VERSION 5.7 ;
  NOWIREEXTENSIONATPIN ON ;
  DIVIDERCHAR "/" ;
  BUSBITCHARS "[]" ;
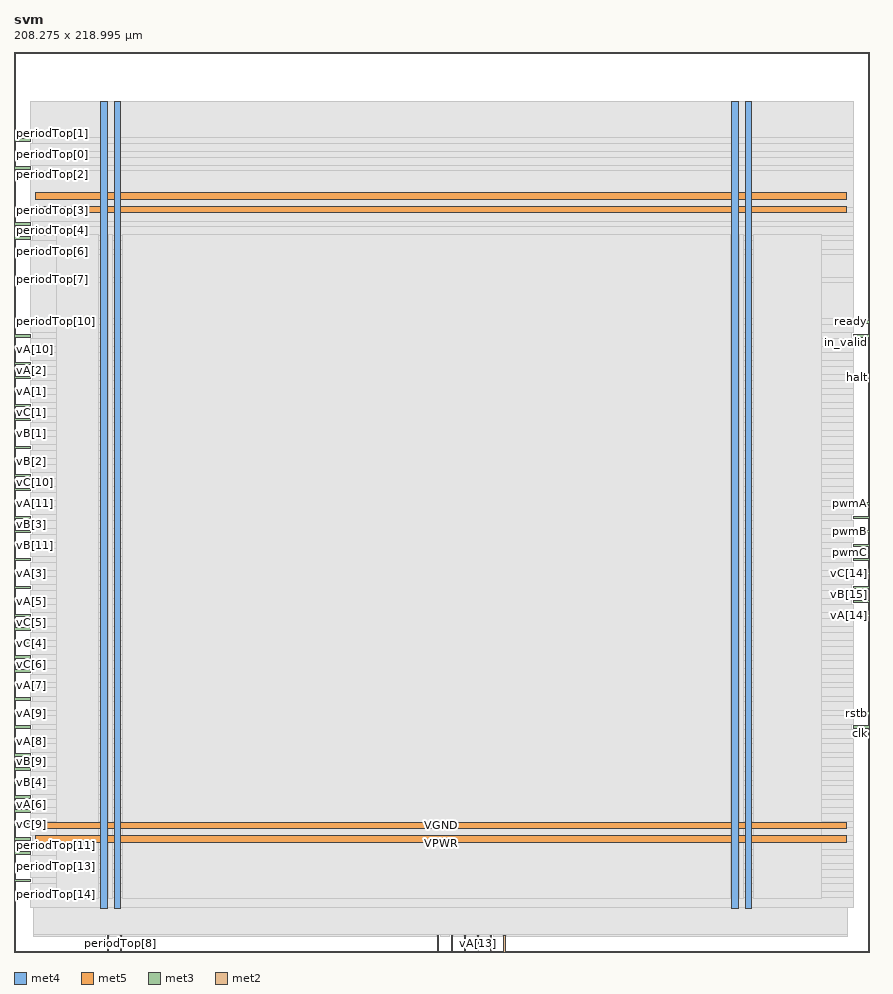
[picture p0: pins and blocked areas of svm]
MACRO svm
  CLASS BLOCK ;
  FOREIGN svm ;
  ORIGIN 0.000 0.000 ;
  SIZE 208.275 BY 218.995 ;
  PIN VGND
    DIRECTION INOUT ;
    USE GROUND ;
    PORT
      LAYER met4 ;
        RECT 24.340 10.640 25.940 206.960 ;
    END
    PORT
      LAYER met4 ;
        RECT 177.940 10.640 179.540 206.960 ;
    END
    PORT
      LAYER met5 ;
        RECT 5.280 30.030 202.640 31.630 ;
    END
    PORT
      LAYER met5 ;
        RECT 5.280 183.210 202.640 184.810 ;
    END
  END VGND
  PIN VPWR
    DIRECTION INOUT ;
    USE POWER ;
    PORT
      LAYER met4 ;
        RECT 21.040 10.640 22.640 206.960 ;
    END
    PORT
      LAYER met4 ;
        RECT 174.640 10.640 176.240 206.960 ;
    END
    PORT
      LAYER met5 ;
        RECT 5.280 26.730 202.640 28.330 ;
    END
    PORT
      LAYER met5 ;
        RECT 5.280 179.910 202.640 181.510 ;
    END
  END VPWR
  PIN clk
    DIRECTION INPUT ;
    USE SIGNAL ;
    ANTENNAGATEAREA 0.852000 ;
    PORT
      LAYER met3 ;
        RECT 204.275 54.440 208.275 55.040 ;
    END
  END clk
  PIN halt
    DIRECTION OUTPUT ;
    USE SIGNAL ;
    ANTENNADIFFAREA 0.445500 ;
    PORT
      LAYER met3 ;
        RECT 204.275 139.440 208.275 140.040 ;
    END
  END halt
  PIN in_valid
    DIRECTION INPUT ;
    USE SIGNAL ;
    ANTENNAGATEAREA 0.196500 ;
    PORT
      LAYER met3 ;
        RECT 204.275 149.640 208.275 150.240 ;
    END
  END in_valid
  PIN periodTop[0]
    DIRECTION INPUT ;
    USE SIGNAL ;
    ANTENNAGATEAREA 0.196500 ;
    PORT
      LAYER met3 ;
        RECT 0.000 193.840 4.000 194.440 ;
    END
  END periodTop[0]
  PIN periodTop[10]
    DIRECTION INPUT ;
    USE SIGNAL ;
    ANTENNAGATEAREA 0.196500 ;
    PORT
      LAYER met3 ;
        RECT 0.000 153.040 4.000 153.640 ;
    END
  END periodTop[10]
  PIN periodTop[11]
    DIRECTION INPUT ;
    USE SIGNAL ;
    ANTENNAGATEAREA 0.196500 ;
    PORT
      LAYER met3 ;
        RECT 0.000 27.240 4.000 27.840 ;
    END
  END periodTop[11]
  PIN periodTop[12]
    DIRECTION INPUT ;
    USE SIGNAL ;
    ANTENNAGATEAREA 0.196500 ;
    PORT
      LAYER met3 ;
        RECT 0.000 23.840 4.000 24.440 ;
    END
  END periodTop[12]
  PIN periodTop[13]
    DIRECTION INPUT ;
    USE SIGNAL ;
    ANTENNAGATEAREA 0.196500 ;
    PORT
      LAYER met3 ;
        RECT 0.000 20.440 4.000 21.040 ;
    END
  END periodTop[13]
  PIN periodTop[14]
    DIRECTION INPUT ;
    USE SIGNAL ;
    ANTENNAGATEAREA 0.742500 ;
    PORT
      LAYER met3 ;
        RECT 0.000 13.640 4.000 14.240 ;
    END
  END periodTop[14]
  PIN periodTop[15]
    DIRECTION INPUT ;
    USE SIGNAL ;
    ANTENNAGATEAREA 0.196500 ;
    PORT
      LAYER met3 ;
        RECT 0.000 17.040 4.000 17.640 ;
    END
  END periodTop[15]
  PIN periodTop[1]
    DIRECTION INPUT ;
    USE SIGNAL ;
    ANTENNAGATEAREA 0.196500 ;
    PORT
      LAYER met3 ;
        RECT 0.000 197.240 4.000 197.840 ;
    END
  END periodTop[1]
  PIN periodTop[2]
    DIRECTION INPUT ;
    USE SIGNAL ;
    ANTENNAGATEAREA 0.196500 ;
    PORT
      LAYER met3 ;
        RECT 0.000 190.440 4.000 191.040 ;
    END
  END periodTop[2]
  PIN periodTop[3]
    DIRECTION INPUT ;
    USE SIGNAL ;
    ANTENNAGATEAREA 0.213000 ;
    PORT
      LAYER met3 ;
        RECT 0.000 180.240 4.000 180.840 ;
    END
  END periodTop[3]
  PIN periodTop[4]
    DIRECTION INPUT ;
    USE SIGNAL ;
    ANTENNAGATEAREA 0.196500 ;
    PORT
      LAYER met3 ;
        RECT 0.000 176.840 4.000 177.440 ;
    END
  END periodTop[4]
  PIN periodTop[5]
    DIRECTION INPUT ;
    USE SIGNAL ;
    ANTENNAGATEAREA 0.213000 ;
    PORT
      LAYER met3 ;
        RECT 0.000 173.440 4.000 174.040 ;
    END
  END periodTop[5]
  PIN periodTop[6]
    DIRECTION INPUT ;
    USE SIGNAL ;
    ANTENNAGATEAREA 0.213000 ;
    PORT
      LAYER met3 ;
        RECT 0.000 170.040 4.000 170.640 ;
    END
  END periodTop[6]
  PIN periodTop[7]
    DIRECTION INPUT ;
    USE SIGNAL ;
    ANTENNAGATEAREA 0.196500 ;
    PORT
      LAYER met3 ;
        RECT 0.000 163.240 4.000 163.840 ;
    END
  END periodTop[7]
  PIN periodTop[8]
    DIRECTION INPUT ;
    USE SIGNAL ;
    ANTENNAGATEAREA 0.196500 ;
    PORT
      LAYER met2 ;
        RECT 25.850 0.000 26.130 4.000 ;
    END
  END periodTop[8]
  PIN periodTop[9]
    DIRECTION INPUT ;
    USE SIGNAL ;
    ANTENNAGATEAREA 0.196500 ;
    PORT
      LAYER met2 ;
        RECT 22.630 0.000 22.910 4.000 ;
    END
  END periodTop[9]
  PIN pwmA
    DIRECTION OUTPUT ;
    USE SIGNAL ;
    ANTENNADIFFAREA 0.445500 ;
    PORT
      LAYER met3 ;
        RECT 204.275 108.840 208.275 109.440 ;
    END
  END pwmA
  PIN pwmB
    DIRECTION OUTPUT ;
    USE SIGNAL ;
    ANTENNADIFFAREA 0.795200 ;
    PORT
      LAYER met3 ;
        RECT 204.275 102.040 208.275 102.640 ;
    END
  END pwmB
  PIN pwmC
    DIRECTION OUTPUT ;
    USE SIGNAL ;
    ANTENNADIFFAREA 0.445500 ;
    PORT
      LAYER met3 ;
        RECT 204.275 98.640 208.275 99.240 ;
    END
  END pwmC
  PIN ready
    DIRECTION OUTPUT ;
    USE SIGNAL ;
    ANTENNADIFFAREA 0.445500 ;
    PORT
      LAYER met3 ;
        RECT 204.275 153.040 208.275 153.640 ;
    END
  END ready
  PIN rstb
    DIRECTION INPUT ;
    USE SIGNAL ;
    ANTENNAGATEAREA 0.196500 ;
    PORT
      LAYER met3 ;
        RECT 204.275 57.840 208.275 58.440 ;
    END
  END rstb
  PIN vA[0]
    DIRECTION INPUT ;
    USE SIGNAL ;
    ANTENNAGATEAREA 0.196500 ;
    PORT
      LAYER met3 ;
        RECT 0.000 149.640 4.000 150.240 ;
    END
  END vA[0]
  PIN vA[10]
    DIRECTION INPUT ;
    USE SIGNAL ;
    ANTENNAGATEAREA 0.196500 ;
    PORT
      LAYER met3 ;
        RECT 0.000 146.240 4.000 146.840 ;
    END
  END vA[10]
  PIN vA[11]
    DIRECTION INPUT ;
    USE SIGNAL ;
    ANTENNAGATEAREA 0.196500 ;
    PORT
      LAYER met3 ;
        RECT 0.000 108.840 4.000 109.440 ;
    END
  END vA[11]
  PIN vA[12]
    DIRECTION INPUT ;
    USE SIGNAL ;
    ANTENNAGATEAREA 0.196500 ;
    PORT
      LAYER met2 ;
        RECT 103.130 0.000 103.410 4.000 ;
    END
  END vA[12]
  PIN vA[13]
    DIRECTION INPUT ;
    USE SIGNAL ;
    ANTENNAGATEAREA 0.196500 ;
    PORT
      LAYER met2 ;
        RECT 112.790 0.000 113.070 4.000 ;
    END
  END vA[13]
  PIN vA[14]
    DIRECTION INPUT ;
    USE SIGNAL ;
    ANTENNAGATEAREA 0.196500 ;
    PORT
      LAYER met3 ;
        RECT 204.275 81.640 208.275 82.240 ;
    END
  END vA[14]
  PIN vA[15]
    DIRECTION INPUT ;
    USE SIGNAL ;
    ANTENNAGATEAREA 0.196500 ;
    PORT
      LAYER met3 ;
        RECT 204.275 95.240 208.275 95.840 ;
    END
  END vA[15]
  PIN vA[1]
    DIRECTION INPUT ;
    USE SIGNAL ;
    ANTENNAGATEAREA 0.196500 ;
    PORT
      LAYER met3 ;
        RECT 0.000 136.040 4.000 136.640 ;
    END
  END vA[1]
  PIN vA[2]
    DIRECTION INPUT ;
    USE SIGNAL ;
    ANTENNAGATEAREA 0.196500 ;
    PORT
      LAYER met3 ;
        RECT 0.000 142.840 4.000 143.440 ;
    END
  END vA[2]
  PIN vA[3]
    DIRECTION INPUT ;
    USE SIGNAL ;
    ANTENNAGATEAREA 0.196500 ;
    PORT
      LAYER met3 ;
        RECT 0.000 91.840 4.000 92.440 ;
    END
  END vA[3]
  PIN vA[4]
    DIRECTION INPUT ;
    USE SIGNAL ;
    ANTENNAGATEAREA 0.196500 ;
    PORT
      LAYER met3 ;
        RECT 0.000 78.240 4.000 78.840 ;
    END
  END vA[4]
  PIN vA[5]
    DIRECTION INPUT ;
    USE SIGNAL ;
    ANTENNAGATEAREA 0.196500 ;
    PORT
      LAYER met3 ;
        RECT 0.000 85.040 4.000 85.640 ;
    END
  END vA[5]
  PIN vA[6]
    DIRECTION INPUT ;
    USE SIGNAL ;
    ANTENNAGATEAREA 0.196500 ;
    PORT
      LAYER met3 ;
        RECT 0.000 34.040 4.000 34.640 ;
    END
  END vA[6]
  PIN vA[7]
    DIRECTION INPUT ;
    USE SIGNAL ;
    ANTENNAGATEAREA 0.196500 ;
    PORT
      LAYER met3 ;
        RECT 0.000 64.640 4.000 65.240 ;
    END
  END vA[7]
  PIN vA[8]
    DIRECTION INPUT ;
    USE SIGNAL ;
    ANTENNAGATEAREA 0.196500 ;
    PORT
      LAYER met3 ;
        RECT 0.000 51.040 4.000 51.640 ;
    END
  END vA[8]
  PIN vA[9]
    DIRECTION INPUT ;
    USE SIGNAL ;
    ANTENNAGATEAREA 0.196500 ;
    PORT
      LAYER met3 ;
        RECT 0.000 57.840 4.000 58.440 ;
    END
  END vA[9]
  PIN vB[0]
    DIRECTION INPUT ;
    USE SIGNAL ;
    ANTENNAGATEAREA 0.196500 ;
    PORT
      LAYER met3 ;
        RECT 0.000 132.640 4.000 133.240 ;
    END
  END vB[0]
  PIN vB[10]
    DIRECTION INPUT ;
    USE SIGNAL ;
    ANTENNAGATEAREA 0.196500 ;
    PORT
      LAYER met3 ;
        RECT 0.000 112.240 4.000 112.840 ;
    END
  END vB[10]
  PIN vB[11]
    DIRECTION INPUT ;
    USE SIGNAL ;
    ANTENNAGATEAREA 0.196500 ;
    PORT
      LAYER met3 ;
        RECT 0.000 98.640 4.000 99.240 ;
    END
  END vB[11]
  PIN vB[12]
    DIRECTION INPUT ;
    USE SIGNAL ;
    ANTENNAGATEAREA 0.196500 ;
    PORT
      LAYER met2 ;
        RECT 106.350 0.000 106.630 4.000 ;
    END
  END vB[12]
  PIN vB[13]
    DIRECTION INPUT ;
    USE SIGNAL ;
    ANTENNAGATEAREA 0.196500 ;
    PORT
      LAYER met2 ;
        RECT 119.230 0.000 119.510 4.000 ;
    END
  END vB[13]
  PIN vB[14]
    DIRECTION INPUT ;
    USE SIGNAL ;
    ANTENNAGATEAREA 0.196500 ;
    PORT
      LAYER met3 ;
        RECT 204.275 105.440 208.275 106.040 ;
    END
  END vB[14]
  PIN vB[15]
    DIRECTION INPUT ;
    USE SIGNAL ;
    ANTENNAGATEAREA 0.196500 ;
    PORT
      LAYER met3 ;
        RECT 204.275 85.040 208.275 85.640 ;
    END
  END vB[15]
  PIN vB[1]
    DIRECTION INPUT ;
    USE SIGNAL ;
    ANTENNAGATEAREA 0.196500 ;
    PORT
      LAYER met3 ;
        RECT 0.000 125.840 4.000 126.440 ;
    END
  END vB[1]
  PIN vB[2]
    DIRECTION INPUT ;
    USE SIGNAL ;
    ANTENNAGATEAREA 0.196500 ;
    PORT
      LAYER met3 ;
        RECT 0.000 119.040 4.000 119.640 ;
    END
  END vB[2]
  PIN vB[3]
    DIRECTION INPUT ;
    USE SIGNAL ;
    ANTENNAGATEAREA 0.196500 ;
    PORT
      LAYER met3 ;
        RECT 0.000 102.040 4.000 102.640 ;
    END
  END vB[3]
  PIN vB[4]
    DIRECTION INPUT ;
    USE SIGNAL ;
    ANTENNAGATEAREA 0.196500 ;
    PORT
      LAYER met3 ;
        RECT 0.000 40.840 4.000 41.440 ;
    END
  END vB[4]
  PIN vB[5]
    DIRECTION INPUT ;
    USE SIGNAL ;
    ANTENNAGATEAREA 0.196500 ;
    PORT
      LAYER met3 ;
        RECT 0.000 88.440 4.000 89.040 ;
    END
  END vB[5]
  PIN vB[6]
    DIRECTION INPUT ;
    USE SIGNAL ;
    ANTENNAGATEAREA 0.196500 ;
    PORT
      LAYER met3 ;
        RECT 0.000 61.240 4.000 61.840 ;
    END
  END vB[6]
  PIN vB[7]
    DIRECTION INPUT ;
    USE SIGNAL ;
    ANTENNAGATEAREA 0.196500 ;
    PORT
      LAYER met3 ;
        RECT 0.000 37.440 4.000 38.040 ;
    END
  END vB[7]
  PIN vB[8]
    DIRECTION INPUT ;
    USE SIGNAL ;
    ANTENNAGATEAREA 0.196500 ;
    PORT
      LAYER met3 ;
        RECT 0.000 54.440 4.000 55.040 ;
    END
  END vB[8]
  PIN vB[9]
    DIRECTION INPUT ;
    USE SIGNAL ;
    ANTENNAGATEAREA 0.196500 ;
    PORT
      LAYER met3 ;
        RECT 0.000 47.640 4.000 48.240 ;
    END
  END vB[9]
  PIN vC[0]
    DIRECTION INPUT ;
    USE SIGNAL ;
    ANTENNAGATEAREA 0.213000 ;
    PORT
      LAYER met3 ;
        RECT 0.000 139.440 4.000 140.040 ;
    END
  END vC[0]
  PIN vC[10]
    DIRECTION INPUT ;
    USE SIGNAL ;
    ANTENNAGATEAREA 0.196500 ;
    PORT
      LAYER met3 ;
        RECT 0.000 115.640 4.000 116.240 ;
    END
  END vC[10]
  PIN vC[11]
    DIRECTION INPUT ;
    USE SIGNAL ;
    ANTENNAGATEAREA 0.196500 ;
    PORT
      LAYER met3 ;
        RECT 0.000 95.240 4.000 95.840 ;
    END
  END vC[11]
  PIN vC[12]
    DIRECTION INPUT ;
    USE SIGNAL ;
    ANTENNAGATEAREA 0.196500 ;
    PORT
      LAYER met2 ;
        RECT 109.570 0.000 109.850 4.000 ;
    END
  END vC[12]
  PIN vC[13]
    DIRECTION INPUT ;
    USE SIGNAL ;
    ANTENNAGATEAREA 0.196500 ;
    PORT
      LAYER met2 ;
        RECT 116.010 0.000 116.290 4.000 ;
    END
  END vC[13]
  PIN vC[14]
    DIRECTION INPUT ;
    USE SIGNAL ;
    ANTENNAGATEAREA 0.196500 ;
    PORT
      LAYER met3 ;
        RECT 204.275 91.840 208.275 92.440 ;
    END
  END vC[14]
  PIN vC[15]
    DIRECTION INPUT ;
    USE SIGNAL ;
    ANTENNAGATEAREA 0.196500 ;
    PORT
      LAYER met3 ;
        RECT 204.275 88.440 208.275 89.040 ;
    END
  END vC[15]
  PIN vC[1]
    DIRECTION INPUT ;
    USE SIGNAL ;
    ANTENNAGATEAREA 0.213000 ;
    PORT
      LAYER met3 ;
        RECT 0.000 129.240 4.000 129.840 ;
    END
  END vC[1]
  PIN vC[2]
    DIRECTION INPUT ;
    USE SIGNAL ;
    ANTENNAGATEAREA 0.196500 ;
    PORT
      LAYER met3 ;
        RECT 0.000 122.440 4.000 123.040 ;
    END
  END vC[2]
  PIN vC[3]
    DIRECTION INPUT ;
    USE SIGNAL ;
    ANTENNAGATEAREA 0.196500 ;
    PORT
      LAYER met3 ;
        RECT 0.000 105.440 4.000 106.040 ;
    END
  END vC[3]
  PIN vC[4]
    DIRECTION INPUT ;
    USE SIGNAL ;
    ANTENNAGATEAREA 0.196500 ;
    PORT
      LAYER met3 ;
        RECT 0.000 74.840 4.000 75.440 ;
    END
  END vC[4]
  PIN vC[5]
    DIRECTION INPUT ;
    USE SIGNAL ;
    ANTENNAGATEAREA 0.196500 ;
    PORT
      LAYER met3 ;
        RECT 0.000 81.640 4.000 82.240 ;
    END
  END vC[5]
  PIN vC[6]
    DIRECTION INPUT ;
    USE SIGNAL ;
    ANTENNAGATEAREA 0.196500 ;
    PORT
      LAYER met3 ;
        RECT 0.000 68.040 4.000 68.640 ;
    END
  END vC[6]
  PIN vC[7]
    DIRECTION INPUT ;
    USE SIGNAL ;
    ANTENNAGATEAREA 0.196500 ;
    PORT
      LAYER met3 ;
        RECT 0.000 71.440 4.000 72.040 ;
    END
  END vC[7]
  PIN vC[8]
    DIRECTION INPUT ;
    USE SIGNAL ;
    ANTENNAGATEAREA 0.196500 ;
    PORT
      LAYER met3 ;
        RECT 0.000 44.240 4.000 44.840 ;
    END
  END vC[8]
  PIN vC[9]
    DIRECTION INPUT ;
    USE SIGNAL ;
    ANTENNAGATEAREA 0.213000 ;
    PORT
      LAYER met3 ;
        RECT 0.000 30.640 4.000 31.240 ;
    END
  END vC[9]
  OBS
      LAYER li1 ;
        RECT 5.520 10.795 202.400 206.805 ;
      LAYER met1 ;
        RECT 4.670 10.240 202.790 206.960 ;
      LAYER met2 ;
        RECT 4.690 4.280 202.770 206.905 ;
        RECT 4.690 3.670 22.350 4.280 ;
        RECT 23.190 3.670 25.570 4.280 ;
        RECT 26.410 3.670 102.850 4.280 ;
        RECT 103.690 3.670 106.070 4.280 ;
        RECT 106.910 3.670 109.290 4.280 ;
        RECT 110.130 3.670 112.510 4.280 ;
        RECT 113.350 3.670 115.730 4.280 ;
        RECT 116.570 3.670 118.950 4.280 ;
        RECT 119.790 3.670 202.770 4.280 ;
      LAYER met3 ;
        RECT 3.990 198.240 204.275 206.885 ;
        RECT 4.400 196.840 204.275 198.240 ;
        RECT 3.990 194.840 204.275 196.840 ;
        RECT 4.400 193.440 204.275 194.840 ;
        RECT 3.990 191.440 204.275 193.440 ;
        RECT 4.400 190.040 204.275 191.440 ;
        RECT 3.990 181.240 204.275 190.040 ;
        RECT 4.400 179.840 204.275 181.240 ;
        RECT 3.990 177.840 204.275 179.840 ;
        RECT 4.400 176.440 204.275 177.840 ;
        RECT 3.990 174.440 204.275 176.440 ;
        RECT 4.400 173.040 204.275 174.440 ;
        RECT 3.990 171.040 204.275 173.040 ;
        RECT 4.400 169.640 204.275 171.040 ;
        RECT 3.990 164.240 204.275 169.640 ;
        RECT 4.400 162.840 204.275 164.240 ;
        RECT 3.990 154.040 204.275 162.840 ;
        RECT 4.400 152.640 203.875 154.040 ;
        RECT 3.990 150.640 204.275 152.640 ;
        RECT 4.400 149.240 203.875 150.640 ;
        RECT 3.990 147.240 204.275 149.240 ;
        RECT 4.400 145.840 204.275 147.240 ;
        RECT 3.990 143.840 204.275 145.840 ;
        RECT 4.400 142.440 204.275 143.840 ;
        RECT 3.990 140.440 204.275 142.440 ;
        RECT 4.400 139.040 203.875 140.440 ;
        RECT 3.990 137.040 204.275 139.040 ;
        RECT 4.400 135.640 204.275 137.040 ;
        RECT 3.990 133.640 204.275 135.640 ;
        RECT 4.400 132.240 204.275 133.640 ;
        RECT 3.990 130.240 204.275 132.240 ;
        RECT 4.400 128.840 204.275 130.240 ;
        RECT 3.990 126.840 204.275 128.840 ;
        RECT 4.400 125.440 204.275 126.840 ;
        RECT 3.990 123.440 204.275 125.440 ;
        RECT 4.400 122.040 204.275 123.440 ;
        RECT 3.990 120.040 204.275 122.040 ;
        RECT 4.400 118.640 204.275 120.040 ;
        RECT 3.990 116.640 204.275 118.640 ;
        RECT 4.400 115.240 204.275 116.640 ;
        RECT 3.990 113.240 204.275 115.240 ;
        RECT 4.400 111.840 204.275 113.240 ;
        RECT 3.990 109.840 204.275 111.840 ;
        RECT 4.400 108.440 203.875 109.840 ;
        RECT 3.990 106.440 204.275 108.440 ;
        RECT 4.400 105.040 203.875 106.440 ;
        RECT 3.990 103.040 204.275 105.040 ;
        RECT 4.400 101.640 203.875 103.040 ;
        RECT 3.990 99.640 204.275 101.640 ;
        RECT 4.400 98.240 203.875 99.640 ;
        RECT 3.990 96.240 204.275 98.240 ;
        RECT 4.400 94.840 203.875 96.240 ;
        RECT 3.990 92.840 204.275 94.840 ;
        RECT 4.400 91.440 203.875 92.840 ;
        RECT 3.990 89.440 204.275 91.440 ;
        RECT 4.400 88.040 203.875 89.440 ;
        RECT 3.990 86.040 204.275 88.040 ;
        RECT 4.400 84.640 203.875 86.040 ;
        RECT 3.990 82.640 204.275 84.640 ;
        RECT 4.400 81.240 203.875 82.640 ;
        RECT 3.990 79.240 204.275 81.240 ;
        RECT 4.400 77.840 204.275 79.240 ;
        RECT 3.990 75.840 204.275 77.840 ;
        RECT 4.400 74.440 204.275 75.840 ;
        RECT 3.990 72.440 204.275 74.440 ;
        RECT 4.400 71.040 204.275 72.440 ;
        RECT 3.990 69.040 204.275 71.040 ;
        RECT 4.400 67.640 204.275 69.040 ;
        RECT 3.990 65.640 204.275 67.640 ;
        RECT 4.400 64.240 204.275 65.640 ;
        RECT 3.990 62.240 204.275 64.240 ;
        RECT 4.400 60.840 204.275 62.240 ;
        RECT 3.990 58.840 204.275 60.840 ;
        RECT 4.400 57.440 203.875 58.840 ;
        RECT 3.990 55.440 204.275 57.440 ;
        RECT 4.400 54.040 203.875 55.440 ;
        RECT 3.990 52.040 204.275 54.040 ;
        RECT 4.400 50.640 204.275 52.040 ;
        RECT 3.990 48.640 204.275 50.640 ;
        RECT 4.400 47.240 204.275 48.640 ;
        RECT 3.990 45.240 204.275 47.240 ;
        RECT 4.400 43.840 204.275 45.240 ;
        RECT 3.990 41.840 204.275 43.840 ;
        RECT 4.400 40.440 204.275 41.840 ;
        RECT 3.990 38.440 204.275 40.440 ;
        RECT 4.400 37.040 204.275 38.440 ;
        RECT 3.990 35.040 204.275 37.040 ;
        RECT 4.400 33.640 204.275 35.040 ;
        RECT 3.990 31.640 204.275 33.640 ;
        RECT 4.400 30.240 204.275 31.640 ;
        RECT 3.990 28.240 204.275 30.240 ;
        RECT 4.400 26.840 204.275 28.240 ;
        RECT 3.990 24.840 204.275 26.840 ;
        RECT 4.400 23.440 204.275 24.840 ;
        RECT 3.990 21.440 204.275 23.440 ;
        RECT 4.400 20.040 204.275 21.440 ;
        RECT 3.990 18.040 204.275 20.040 ;
        RECT 4.400 16.640 204.275 18.040 ;
        RECT 3.990 14.640 204.275 16.640 ;
        RECT 4.400 13.240 204.275 14.640 ;
        RECT 3.990 10.715 204.275 13.240 ;
      LAYER met4 ;
        RECT 10.415 13.095 20.640 174.585 ;
        RECT 23.040 13.095 23.940 174.585 ;
        RECT 26.340 13.095 174.240 174.585 ;
        RECT 176.640 13.095 177.540 174.585 ;
        RECT 179.940 13.095 196.585 174.585 ;
  END
END svm
END LIBRARY

